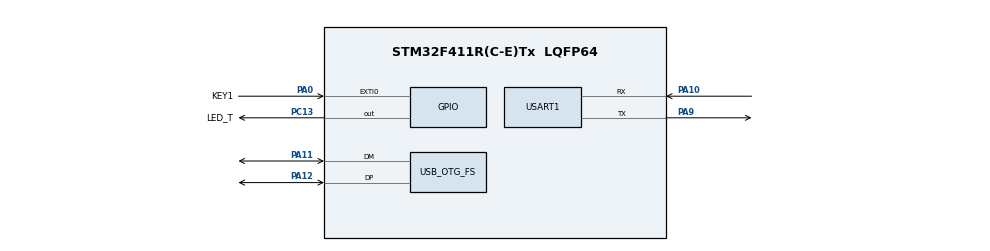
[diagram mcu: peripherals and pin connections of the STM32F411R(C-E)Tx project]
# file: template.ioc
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Mcu.Family=STM32F4
Mcu.Name=STM32F411R(C-E)Tx
Mcu.Package=LQFP64
NVIC.EXTI0_IRQn=true\:0\:0\:false\:false\:true\:true\:true\:true
NVIC.OTG_FS_IRQn=true\:0\:0\:false\:false\:true\:false\:true\:true
NVIC.PriorityGroup=NVIC_PRIORITYGROUP_4
PA0-WKUP.GPIO_Label=KEY1
PA0-WKUP.GPIO_ModeDefaultEXTI=GPIO_MODE_IT_FALLING
PA0-WKUP.GPIO_PuPd=GPIO_PULLUP
PA0-WKUP.Signal=GPXTI0
PA10.Mode=Asynchronous
PA10.Signal=USART1_RX
PA11.Mode=Device_Only
PA11.Signal=USB_OTG_FS_DM
PA12.Mode=Device_Only
PA12.Signal=USB_OTG_FS_DP
PA13.Mode=Serial_Wire
PA13.Signal=SYS_JTMS-SWDIO
PA14.Mode=Serial_Wire
PA14.Signal=SYS_JTCK-SWCLK
PA9.Mode=Asynchronous
PA9.Signal=USART1_TX
PC13-ANTI_TAMP.GPIO_Label=LED_T
PC13-ANTI_TAMP.Signal=GPIO_Output
PC14-OSC32_IN.Mode=LSE-External-Oscillator
PC14-OSC32_IN.Signal=RCC_OSC32_IN
PC15-OSC32_OUT.Mode=LSE-External-Oscillator
PC15-OSC32_OUT.Signal=RCC_OSC32_OUT
PH0\ -\ OSC_IN.Mode=HSE-External-Oscillator
PH0\ -\ OSC_IN.Signal=RCC_OSC_IN
PH1\ -\ OSC_OUT.Mode=HSE-External-Oscillator
PH1\ -\ OSC_OUT.Signal=RCC_OSC_OUT
ProjectManager.HeapSize=0x800
ProjectManager.StackSize=0x1000
ProjectManager.TargetToolchain=MDK-ARM V5.32
RCC.48MHZClocksFreq_Value=48000000
RCC.AHBFreq_Value=72000000
RCC.APB1CLKDivider=RCC_HCLK_DIV2
RCC.APB1Freq_Value=36000000
RCC.APB1TimFreq_Value=72000000
RCC.APB2Freq_Value=72000000
RCC.APB2TimFreq_Value=72000000
RCC.CortexFreq_Value=72000000
RCC.HCLKFreq_Value=72000000
RCC.HSE_VALUE=25000000
RCC.HSI_VALUE=16000000
RCC.PLLM=25
RCC.PLLN=144
RCC.PLLQ=3
RCC.SYSCLKFreq_VALUE=72000000
RCC.SYSCLKSource=RCC_SYSCLKSOURCE_PLLCLK
RCC.VCOOutputFreq_Value=144000000
USART1.VirtualMode=VM_ASYNC
USB_DEVICE.CLASS_NAME_FS=MSC
USB_DEVICE.MSC_MEDIA_PACKET=512
USB_DEVICE.USBD_MAX_STR_DESC_SIZ=512
USB_DEVICE.VirtualMode=Msc
USB_DEVICE.VirtualModeFS=Msc_FS
USB_OTG_FS.VirtualMode=Device_Only
VP_USB_DEVICE_VS_USB_DEVICE_MSC_FS.Mode=MSC_FS
board=custom

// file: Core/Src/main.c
/* USER CODE BEGIN Header */
/**
  ******************************************************************************
  * @file           : main.c
  * @brief          : Main program body
  ******************************************************************************
  * @attention
  *
  * Copyright (c) 2023 STMicroelectronics.
  * All rights reserved.
  *
  * This software is licensed under terms that can be found in the LICENSE file
  * in the root directory of this software component.
  * If no LICENSE file comes with this software, it is provided AS-IS.
  *
  ******************************************************************************
  */
/* USER CODE END Header */
#include "main.h"
#include "usart.h"
#include "gpio.h"

/* USER CODE BEGIN Includes */
#include <stdio.h>
/* USER CODE END Includes */

/* USER CODE BEGIN PV */
uint8_t blink_mode = 0;

/* USER CODE END PV */

void SystemClock_Config(void);

int main(void)
{

  /* MCU Configuration--------------------------------------------------------*/

  /* Reset of all peripherals, Initializes the Flash interface and the Systick. */
  HAL_Init();

  /* Configure the system clock */
  SystemClock_Config();

  /* Initialize all configured peripherals */
  MX_GPIO_Init();
  MX_USART1_UART_Init();

  /* Infinite loop */
  while (1)
  {

    /* USER CODE BEGIN 3 */
		if(blink_mode == 0)
		{
			HAL_GPIO_TogglePin(LED_T_GPIO_Port, LED_T_Pin);
			printf("mode0\r\n");
			HAL_Delay(500);
		}
		else if(blink_mode == 1)
		{
			HAL_GPIO_TogglePin(LED_T_GPIO_Port, LED_T_Pin);
			printf("mode1\r\n");
			HAL_Delay(250);
		}
		else if(blink_mode == 2)
		{
			HAL_GPIO_TogglePin(LED_T_GPIO_Port, LED_T_Pin);
			printf("mode2\r\n");
			HAL_Delay(100);
		}
		else if(blink_mode == 3)
		{
      HAL_GPIO_WritePin(LED_T_GPIO_Port, LED_T_Pin, GPIO_PIN_RESET);
			printf("close\r\n");
			HAL_Delay(500);
		}

  }
  /* USER CODE END 3 */
}

void SystemClock_Config(void)
{
  RCC_OscInitTypeDef RCC_OscInitStruct = {0};
  RCC_ClkInitTypeDef RCC_ClkInitStruct = {0};

  /** Configure the main internal regulator output voltage
  */
  __HAL_RCC_PWR_CLK_ENABLE();
  __HAL_PWR_VOLTAGESCALING_CONFIG(PWR_REGULATOR_VOLTAGE_SCALE1);

  /** Initializes the RCC Oscillators according to the specified parameters
  * in the RCC_OscInitTypeDef structure.
  */
  RCC_OscInitStruct.OscillatorType = RCC_OSCILLATORTYPE_HSE;
  RCC_OscInitStruct.HSEState = RCC_HSE_ON;
  RCC_OscInitStruct.PLL.PLLState = RCC_PLL_ON;
  RCC_OscInitStruct.PLL.PLLSource = RCC_PLLSOURCE_HSE;
  RCC_OscInitStruct.PLL.PLLM = 12;
  RCC_OscInitStruct.PLL.PLLN = 96;
  RCC_OscInitStruct.PLL.PLLP = RCC_PLLP_DIV2;
  RCC_OscInitStruct.PLL.PLLQ = 4;
  if (HAL_RCC_OscConfig(&RCC_OscInitStruct) != HAL_OK)
  {
    Error_Handler();
  }

  /** Initializes the CPU, AHB and APB buses clocks
  */
  RCC_ClkInitStruct.ClockType = RCC_CLOCKTYPE_HCLK|RCC_CLOCKTYPE_SYSCLK
                              |RCC_CLOCKTYPE_PCLK1|RCC_CLOCKTYPE_PCLK2;
  RCC_ClkInitStruct.SYSCLKSource = RCC_SYSCLKSOURCE_PLLCLK;
  RCC_ClkInitStruct.AHBCLKDivider = RCC_SYSCLK_DIV1;
  RCC_ClkInitStruct.APB1CLKDivider = RCC_HCLK_DIV2;
  RCC_ClkInitStruct.APB2CLKDivider = RCC_HCLK_DIV1;

  if (HAL_RCC_ClockConfig(&RCC_ClkInitStruct, FLASH_LATENCY_3) != HAL_OK)
  {
    Error_Handler();
  }
}

void Error_Handler(void)
{
  __disable_irq();
  while (1)
  {
  }
}
